PROGRAM p02_ura
VAR
	M0: BOOL;
END_VAR

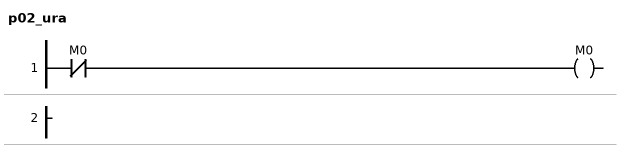
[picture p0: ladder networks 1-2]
// NETWORK 1
M0 := NOT M0;

// NETWORK 2

END_PROGRAM
